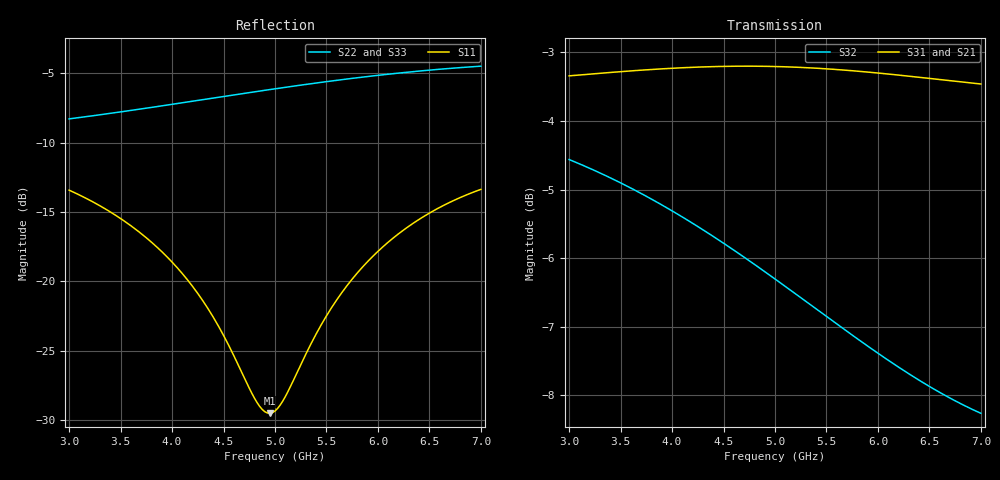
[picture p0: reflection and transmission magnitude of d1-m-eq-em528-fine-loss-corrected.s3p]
! yapnr Order 0 prediction d1-m-eq-em528-fine: predictions/D1/variants/d1-star-m-eq-em528/fine.s3p, loss-corrected
! substrate M-eq-em528; coupon model OSHPARK-4L-EM528; correction: ratio (port line)
! |S21|, |S31| (and S12, S13) scaled, phases kept; 50 ohm, e^(+jwt)
# GHz S RI R 50
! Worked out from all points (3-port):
!   161 points, 3 GHz to 7 GHz, reference 50 ohm
!   strongest paths, dB at 3 GHz, 4 GHz, 5 GHz, 6 GHz, 7 GHz:
!     S31: -3.3, -3.2, -3.2, -3.3, -3.5
!     S21: -3.3, -3.2, -3.2, -3.3, -3.5
!     S32: -4.6, -5.3, -6.3, -7.4, -8.3
!   lowest |S11| = -29.5 dB at 4.95 GHz (marker M1), VSWR 1.07, Z = 46.8 + j0.342 ohm
!   |S11| at or under -10 dB: start of sweep to end of sweep
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3  -0.1477 0.1537  0.0847 -0.6753  0.0847 -0.6753
   0.0846 -0.6753  0.0748 0.3779  -0.1725 -0.5657
   0.0846 -0.6753  -0.1725 -0.5657  0.0748 0.3779
4.05  -0.0571 0.0963  -0.2698 -0.6347  -0.2698 -0.6347
      -0.2698 -0.6346  0.328 0.2896  -0.4322 -0.3234
      -0.2698 -0.6346  -0.4322 -0.3234  0.328 0.2896
4.4  -0.0397 0.0628  -0.379 -0.5781  -0.379 -0.5781
     -0.379 -0.578  0.4 0.223  -0.4706 -0.2209
     -0.379 -0.578  -0.4706 -0.2209  0.4 0.223
4.825  -0.0322 0.0173  -0.4952 -0.483  -0.4952 -0.483
       -0.4952 -0.4829  0.4685 0.1207  -0.4848 -0.0977
       -0.4952 -0.4829  -0.4848 -0.0977  0.4685 0.1207
4.95  -0.0332 0.00365  -0.525 -0.4501  -0.525 -0.4501
      -0.5249 -0.45  0.4837 0.0869  -0.4829 -0.0631
      -0.5249 -0.45  -0.4829 -0.0631  0.4837 0.0869
5  -0.034 -0.00175  -0.5363 -0.4364  -0.5363 -0.4364
   -0.5362 -0.4363  0.4891 0.0729  -0.4814 -0.0496
   -0.5362 -0.4363  -0.4814 -0.0496  0.4891 0.0729
5.5  -0.0546 -0.0515  -0.6269 -0.2852  -0.6269 -0.2852
     -0.6268 -0.2851  0.5195 -0.0748  -0.4485 0.0736
     -0.6268 -0.2851  -0.4485 0.0736  0.5195 -0.0748
5.875  -0.0832 -0.0797  -0.6663 -0.1601  -0.6663 -0.1601
       -0.6662 -0.16  0.5124 -0.1896  -0.4072 0.1495
       -0.6662 -0.16  -0.4072 0.1495  0.5124 -0.1896
6.375  -0.1326 -0.0982  -0.6792 0.0113  -0.6792 0.0113
       -0.6792 0.0113  0.4634 -0.3351  -0.3401 0.228
       -0.6792 0.0113  -0.3401 0.228  0.4634 -0.3351
7  -0.197 -0.085  -0.6358 0.2159  -0.6358 0.2159
   -0.6356 0.216  0.3482 -0.4847  -0.2489 0.2954
   -0.6356 0.216  -0.2489 0.2954  0.3482 -0.4847
